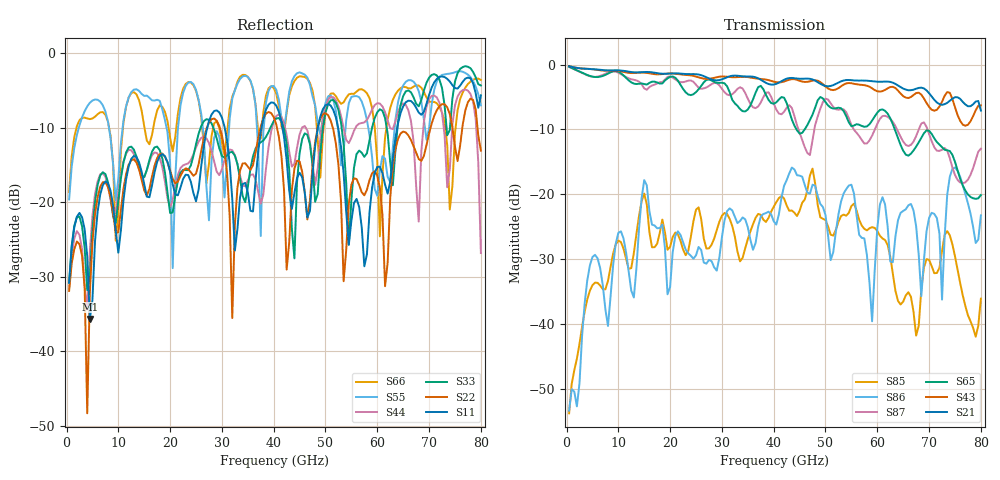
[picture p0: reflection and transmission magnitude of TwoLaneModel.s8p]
! File created by SignalIntegrity v1.5.1: Signal and Power Integrity Tools
! https://github.com/Nubis-Communications/SignalIntegrity
# MHz S MA R 50.0
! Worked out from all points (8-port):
!   160 points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, 500 MHz to 80 GHz, reference 50 ohm
!   strongest paths, dB at 500 MHz, 20.5 GHz, 40.5 GHz, 60.5 GHz, 80 GHz:
!     S21: -0.2, -1.3, -3.0, -2.6, -7.1
!     S43: -0.2, -1.4, -2.7, -4.2, -6.3
!     S65: -0.3, -1.8, -5.8, -7.0, -20.1
!     S87: -0.3, -2.0, -6.9, -8.4, -13.0
!     S86: -53.4, -28.9, -24.7, -21.6, -23.3
!     S85: -53.8, -26.6, -21.2, -26.4, -36.1
!   lowest |S11| = -35.7 dB at 4.5 GHz (marker M1), VSWR 1.03, Z = 50.6 + j1.53 ohm
!   |S11| at or under -10 dB: start of sweep to 27.17 GHz; 30.55 GHz to 37.65 GHz (7.105 GHz wide, 20.8 % of centre); 52.44 GHz to 63.84 GHz (11.41 GHz wide, 19.6 % of centre) (the widest 3 of 4)
